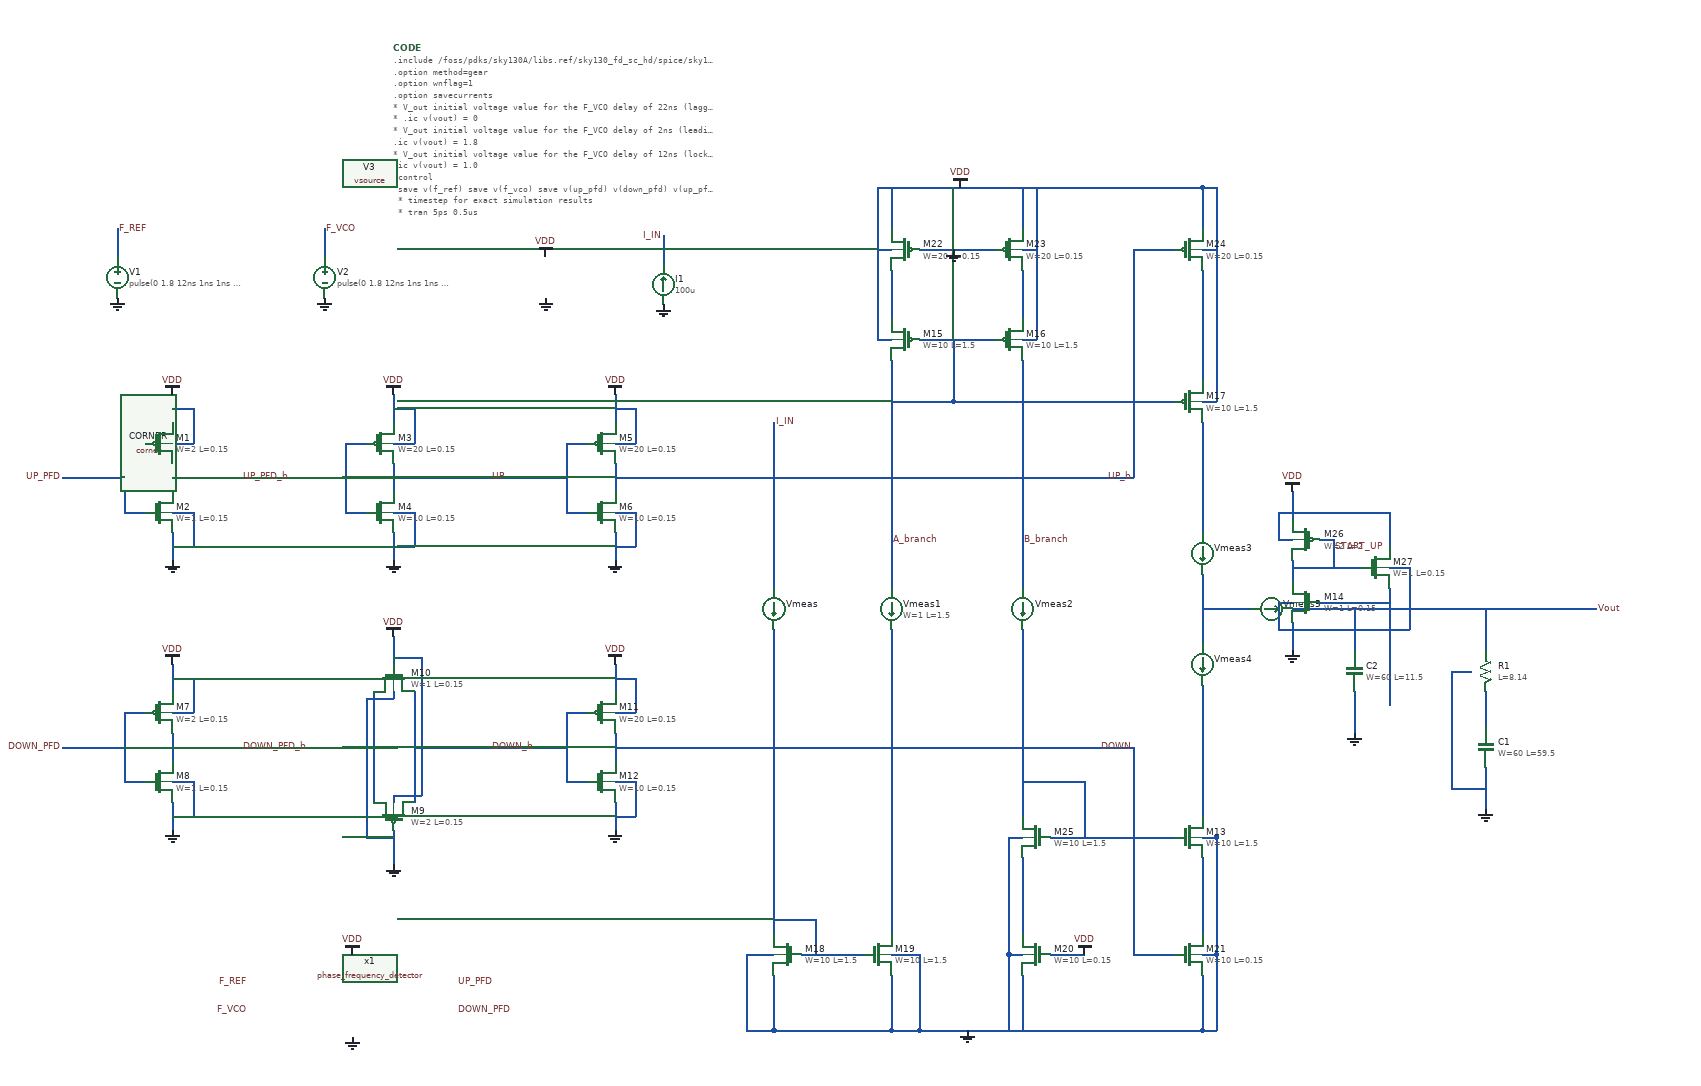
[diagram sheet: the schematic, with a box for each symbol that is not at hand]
v {xschem version=3.4.5 file_version=1.2
}
G {}
K {}
V {}
S {}
E {}
B 2 2530 -2160 3560 -1860 {flags=graph
y1=0
y2=1.8
ypos1=0
ypos2=2
divy=5
subdivy=1
unity=1
x1=2.1214896e-07
x2=2.1451015e-07
divx=5
subdivx=1
xlabmag=1.0
ylabmag=1.0


dataset=-1
unitx=1
logx=0
logy=0








linewidth_mult=5


color="6 7"
node="f_ref
f_vco"}
B 2 2530 -1840 3560 -1540 {flags=graph
y1=-0.038
y2=1.9
ypos1=0
ypos2=2
divy=5
subdivy=1
unity=1
x1=2.1214896e-07
x2=2.1451015e-07
divx=5
subdivx=1
xlabmag=1.0
ylabmag=1.0


dataset=-1
unitx=1
logx=0
logy=0








linewidth_mult=5


color="6 7"
node="up_pfd
down_pfd"}
B 2 2530 -1520 3560 -1220 {flags=graph
y1=-0.17312349
y2=1.9868765
ypos1=0
ypos2=2
divy=5
subdivy=1
unity=1
x1=2.1214896e-07
x2=2.1451015e-07
divx=5
subdivx=1
xlabmag=1.0
ylabmag=1.0


dataset=-1
unitx=1
logx=0
logy=0








linewidth_mult=5


color="6 7"
node="up_pfd_b
down_pfd_b"}
B 2 2530 -1200 3560 -900 {flags=graph
y1=-0.015
y2=1.9
ypos1=0
ypos2=2
divy=5
subdivy=1
unity=1
x1=2.1214896e-07
x2=2.1451015e-07
divx=5
subdivx=1
xlabmag=1.0
ylabmag=1.0


dataset=-1
unitx=1
logx=0
logy=0








linewidth_mult=5


color="6 7"
node="up
down_b"}
B 2 2530 -880 3560 -580 {flags=graph
y1=-0.012
y2=1.9
ypos1=0
ypos2=2
divy=5
subdivy=1
unity=1
x1=2.1214896e-07
x2=2.1451015e-07
divx=5
subdivx=1
xlabmag=1.0
ylabmag=1.0


dataset=-1
unitx=1
logx=0
logy=0








linewidth_mult=5


color="6 7"
node="up_b
down"}
B 2 3740 -2160 4770 -1860 {flags=graph
y1=-0.00062
y2=0.0001
ypos1=0
ypos2=2
divy=5
subdivy=1
unity=1
x1=2.1214896e-07
x2=2.1451015e-07
divx=5
subdivx=1
xlabmag=1.0
ylabmag=1.0


dataset=-1
unitx=1
logx=0
logy=0








linewidth_mult=5



color="6 7"
node="i(vmeas3)
i(vmeas4)"}
B 2 3740 -1840 4770 -1540 {flags=graph
y1=4.1e-15
y2=0.0016
ypos1=0
ypos2=2
divy=5
subdivy=1
unity=1
x1=2.1214896e-07
x2=2.1451015e-07
divx=5
subdivx=1
xlabmag=1.0
ylabmag=1.0


dataset=-1
unitx=1
logx=0
logy=0








linewidth_mult=5



color="6 7"
node="i(@m.xm24.msky130_fd_pr__pfet_01v8[id])
i(@m.xm21.msky130_fd_pr__nfet_01v8[id])"}
B 2 3740 -1520 4770 -1220 {flags=graph
y1=3.1e-12
y2=5.6e-05
ypos1=0
ypos2=2
divy=5
subdivy=1
unity=1
x1=2.1214896e-07
x2=2.1451015e-07
divx=5
subdivx=1
xlabmag=1.0
ylabmag=1.0


dataset=-1
unitx=1
logx=0
logy=0








linewidth_mult=5


color="6 7"
node="i(@m.xm17.msky130_fd_pr__pfet_01v8[id])
i(@m.xm13.msky130_fd_pr__nfet_01v8[id])"}
B 2 3740 -1200 4770 -900 {flags=graph
y1=-0.00035
y2=0.00021
ypos1=0
ypos2=2
divy=5
subdivy=1
unity=1
x1=2.1214896e-07
x2=2.1451015e-07
divx=5
subdivx=1
xlabmag=1.0
ylabmag=1.0


dataset=-1
unitx=1
logx=0
logy=0








linewidth_mult=5




color=6
node="\\"i(vmeas3) i(vmeas4) - \\""}
B 2 3740 -880 4770 -580 {flags=graph
y1=0.97
y2=1.2
ypos1=0
ypos2=2
divy=5
subdivy=1
unity=1
x1=2.1214896e-07
x2=2.1451015e-07
divx=5
subdivx=1
xlabmag=1.0
ylabmag=1.0


dataset=-1
unitx=1
logx=0
logy=0








linewidth_mult=5



color=6
node=vout}
N 2210 -1310 2210 -1260 {
lab=#net1}
N 2210 -1430 2210 -1370 {
lab=Vout}
N 2210 -1200 2210 -1140 {
lab=GND}
N 2160 -1340 2190 -1340 {
lab=GND}
N 2160 -1340 2160 -1170 {
lab=GND}
N 2160 -1170 2210 -1170 {
lab=GND}
N 2020 -1430 2020 -1370 {
lab=Vout}
N 2020 -1310 2020 -1250 {
lab=GND}
N 230 -1980 230 -1940 {
lab=F_REF}
N 530 -1980 530 -1940 {
lab=F_VCO}
N 1930 -1430 2370 -1430 {
lab=Vout}
N 1020 -1970 1020 -1930 {
lab=I_IN}
N 1800 -1430 1870 -1430 {
lab=#net2}
N 1220 -930 1310 -930 {
lab=#net3}
N 1180 -900 1180 -820 {
lab=GND}
N 1180 -820 1350 -820 {
lab=GND}
N 1140 -930 1180 -930 {
lab=GND}
N 1140 -930 1140 -820 {
lab=GND}
N 1140 -820 1180 -820 {
lab=GND}
N 1390 -930 1390 -820 {
lab=GND}
N 1350 -900 1350 -820 {
lab=GND}
N 1240 -980 1240 -930 {
lab=#net3}
N 1350 -820 1390 -820 {
lab=GND}
N 1180 -1700 1180 -1650 {
lab=I_IN}
N 1180 -1650 1180 -1460 {
lab=I_IN}
N 1620 -2040 1800 -2040 {
lab=VDD}
N 1800 -2040 1820 -2040 {
lab=VDD}
N 1390 -820 1700 -820 {
lab=GND}
N 1700 -820 1800 -820 {
lab=GND}
N 1820 -930 1820 -820 {
lab=GND}
N 1800 -820 1820 -820 {
lab=GND}
N 1800 -1730 1820 -1730 {
lab=VDD}
N 1800 -930 1820 -930 {
lab=GND}
N 1350 -930 1390 -930 {
lab=GND}
N 1330 -2040 1620 -2040 {
lab=VDD}
N 1520 -930 1540 -930 {
lab=GND}
N 1390 -1820 1500 -1820 {
lab=A_branch}
N 1440 -1820 1440 -1730 {
lab=A_branch}
N 1540 -1820 1560 -1820 {
lab=VDD}
N 1800 -1450 1800 -1380 {
lab=#net2}
N 1520 -930 1520 -820 {
lab=GND}
N 1800 -1480 1800 -1450 {
lab=#net2}
N 410 -1620 510 -1620 {
lab=UP_PFD_b}
N 410 -1230 600 -1230 {
lab=DOWN_PFD_b}
N 150 -1230 190 -1230 {
lab=DOWN_PFD}
N 150 -1620 190 -1620 {
lab=UP_PFD}
N 600 -1310 600 -1150 {
lab=DOWN_PFD_b}
N 660 -1310 660 -1150 {
lab=DOWN_b}
N 630 -1390 630 -1350 {
lab=VDD}
N 630 -1160 630 -1150 {
lab=VDD}
N 630 -1160 670 -1160 {
lab=VDD}
N 670 -1360 670 -1160 {
lab=VDD}
N 630 -1360 670 -1360 {
lab=VDD}
N 630 -1310 630 -1300 {
lab=GND}
N 590 -1300 630 -1300 {
lab=GND}
N 590 -1300 590 -1100 {
lab=GND}
N 590 -1100 630 -1100 {
lab=GND}
N 630 -1110 630 -1060 {
lab=GND}
N 310 -1640 310 -1600 {
lab=UP_PFD_b}
N 240 -1670 270 -1670 {
lab=UP_PFD}
N 240 -1670 240 -1570 {
lab=UP_PFD}
N 240 -1570 270 -1570 {
lab=UP_PFD}
N 310 -1230 410 -1230 {
lab=DOWN_PFD_b}
N 190 -1620 240 -1620 {
lab=UP_PFD}
N 310 -1540 310 -1500 {
lab=GND}
N 310 -1740 310 -1700 {
lab=VDD}
N 310 -1670 340 -1670 {
lab=VDD}
N 340 -1720 340 -1670 {
lab=VDD}
N 310 -1720 340 -1720 {
lab=VDD}
N 310 -1570 340 -1570 {
lab=GND}
N 340 -1570 340 -1520 {
lab=GND}
N 310 -1520 340 -1520 {
lab=GND}
N 310 -1250 310 -1210 {
lab=DOWN_PFD_b}
N 240 -1280 270 -1280 {
lab=DOWN_PFD}
N 240 -1280 240 -1180 {
lab=DOWN_PFD}
N 240 -1180 270 -1180 {
lab=DOWN_PFD}
N 310 -1620 410 -1620 {
lab=UP_PFD_b}
N 190 -1230 240 -1230 {
lab=DOWN_PFD}
N 310 -1150 310 -1110 {
lab=GND}
N 310 -1350 310 -1310 {
lab=VDD}
N 310 -1280 340 -1280 {
lab=VDD}
N 340 -1330 340 -1280 {
lab=VDD}
N 310 -1330 340 -1330 {
lab=VDD}
N 310 -1180 340 -1180 {
lab=GND}
N 340 -1180 340 -1130 {
lab=GND}
N 310 -1130 340 -1130 {
lab=GND}
N 630 -1640 630 -1600 {
lab=UP}
N 560 -1670 590 -1670 {
lab=UP_PFD_b}
N 560 -1670 560 -1570 {
lab=UP_PFD_b}
N 560 -1570 590 -1570 {
lab=UP_PFD_b}
N 630 -1540 630 -1500 {
lab=GND}
N 630 -1740 630 -1700 {
lab=VDD}
N 630 -1670 660 -1670 {
lab=VDD}
N 660 -1720 660 -1670 {
lab=VDD}
N 630 -1720 660 -1720 {
lab=VDD}
N 630 -1570 660 -1570 {
lab=GND}
N 660 -1570 660 -1520 {
lab=GND}
N 630 -1520 660 -1520 {
lab=GND}
N 1180 -1030 1180 -960 {
lab=#net3}
N 1180 -1400 1180 -1090 {
lab=#net3}
N 1350 -1030 1350 -960 {
lab=#net4}
N 1350 -1400 1350 -1090 {
lab=#net4}
N 1350 -1730 1440 -1730 {
lab=A_branch}
N 1180 -980 1240 -980 {
lab=#net3}
N 1180 -1090 1180 -1030 {
lab=#net3}
N 1350 -1090 1350 -1030 {
lab=#net4}
N 1440 -1730 1760 -1730 {
lab=A_branch}
N 950 -1640 950 -1600 {
lab=UP_b}
N 880 -1670 910 -1670 {
lab=UP}
N 880 -1670 880 -1570 {
lab=UP}
N 880 -1570 910 -1570 {
lab=UP}
N 950 -1540 950 -1500 {
lab=GND}
N 950 -1740 950 -1700 {
lab=VDD}
N 950 -1670 980 -1670 {
lab=VDD}
N 980 -1720 980 -1670 {
lab=VDD}
N 950 -1720 980 -1720 {
lab=VDD}
N 950 -1570 980 -1570 {
lab=GND}
N 980 -1570 980 -1520 {
lab=GND}
N 950 -1520 980 -1520 {
lab=GND}
N 950 -1250 950 -1210 {
lab=DOWN}
N 880 -1280 910 -1280 {
lab=DOWN_b}
N 880 -1280 880 -1180 {
lab=DOWN_b}
N 880 -1180 910 -1180 {
lab=DOWN_b}
N 950 -1150 950 -1110 {
lab=GND}
N 950 -1350 950 -1310 {
lab=VDD}
N 950 -1280 980 -1280 {
lab=VDD}
N 980 -1330 980 -1280 {
lab=VDD}
N 950 -1330 980 -1330 {
lab=VDD}
N 950 -1180 980 -1180 {
lab=GND}
N 980 -1180 980 -1130 {
lab=GND}
N 950 -1130 980 -1130 {
lab=GND}
N 630 -1620 880 -1620 {
lab=UP}
N 660 -1230 880 -1230 {
lab=DOWN_b}
N 950 -1620 1700 -1620 {
lab=UP_b}
N 950 -1230 1700 -1230 {
lab=DOWN}
N 510 -1620 560 -1620 {
lab=UP_PFD_b}
N 1540 -900 1540 -820 {
lab=GND}
N 1800 -900 1800 -820 {
lab=GND}
N 1800 -1920 1800 -1760 {
lab=#net5}
N 1820 -1920 1820 -1730 {
lab=VDD}
N 1540 -1790 1540 -1460 {
lab=B_branch}
N 1540 -1920 1540 -1850 {
lab=#net6}
N 1350 -1790 1350 -1460 {
lab=A_branch}
N 1350 -1920 1350 -1850 {
lab=#net7}
N 1560 -1920 1560 -1820 {
lab=VDD}
N 1330 -1920 1330 -1820 {
lab=VDD}
N 1330 -1820 1350 -1820 {
lab=VDD}
N 1390 -1950 1500 -1950 {
lab=GND}
N 1540 -1950 1560 -1950 {
lab=VDD}
N 1330 -1950 1350 -1950 {
lab=VDD}
N 1560 -2040 1560 -1920 {
lab=VDD}
N 1330 -2040 1330 -1920 {
lab=VDD}
N 1350 -2040 1350 -1980 {
lab=VDD}
N 1540 -2040 1540 -1980 {
lab=VDD}
N 1800 -1950 1820 -1950 {
lab=VDD}
N 1820 -2040 1820 -1920 {
lab=VDD}
N 1800 -2040 1800 -1980 {
lab=VDD}
N 1800 -1700 1800 -1540 {
lab=#net8}
N 1700 -1950 1700 -1620 {
lab=UP_b}
N 1700 -1950 1760 -1950 {
lab=UP_b}
N 1800 -1100 1820 -1100 {
lab=GND}
N 1520 -1100 1540 -1100 {
lab=GND}
N 1630 -1180 1630 -1100 {
lab=#net9}
N 1540 -1180 1630 -1180 {
lab=#net9}
N 1580 -1100 1760 -1100 {
lab=#net9}
N 1800 -1070 1800 -960 {
lab=#net10}
N 1820 -1100 1820 -930 {
lab=GND}
N 1540 -1070 1540 -960 {
lab=#net11}
N 1820 -1100 1820 -930 {
lab=GND}
N 1520 -1100 1520 -930 {
lab=GND}
N 1540 -1400 1540 -1130 {
lab=#net9}
N 1700 -1230 1700 -930 {
lab=DOWN}
N 1800 -1320 1800 -1130 {
lab=#net12}
N 1700 -930 1760 -930 {
lab=DOWN}
N 1580 -930 1630 -930 {
lab=VDD}
N 1930 -1500 1930 -1470 {
lab=START_UP}
N 1910 -1530 1930 -1530 {
lab=VDD}
N 1910 -1570 1910 -1530 {
lab=VDD}
N 1910 -1570 1930 -1570 {
lab=VDD}
N 1910 -1440 1930 -1440 {
lab=GND}
N 1910 -1440 1910 -1400 {
lab=GND}
N 1910 -1400 1930 -1400 {
lab=GND}
N 1930 -1490 2030 -1490 {
lab=START_UP}
N 2070 -1490 2100 -1490 {
lab=GND}
N 2100 -1490 2100 -1400 {
lab=GND}
N 1930 -1400 2100 -1400 {
lab=GND}
N 1970 -1530 1990 -1530 {
lab=START_UP}
N 1990 -1530 1990 -1490 {
lab=START_UP}
N 2070 -1460 2070 -1290 {
lab=#net3}
N 1970 -1440 2070 -1440 {
lab=#net3}
N 1930 -1570 2070 -1570 {
lab=VDD}
N 2070 -1570 2070 -1520 {
lab=VDD}
N 1930 -1410 1930 -1370 {
lab=GND}
N 1930 -1600 1930 -1560 {
lab=VDD}
C {sky130_fd_pr/corner.sym} 470 -2240 0 0 {name=CORNER only_toplevel=false corner=tt}
C {devices/code.sym} 630 -2241.25 0 0 {name=CODE only_toplevel=false value="

.include /foss/pdks/sky130A/libs.ref/sky130_fd_sc_hd/spice/sky130_fd_sc_hd.spice

.option method=gear
.option wnflag=1
.option savecurrents

* V_out initial voltage value for the F_VCO delay of 22ns (lagging)
* .ic v(vout) = 0

* V_out initial voltage value for the F_VCO delay of 2ns  (leading)
.ic v(vout) = 1.8

* V_out initial voltage value for the F_VCO delay of 12ns (lock condition)
.ic v(vout) = 1.0

.control
  save v(f_ref) save v(f_vco) save v(up_pfd) v(down_pfd) v(up_pfd_b) v(down_pfd_b) v(up) v(up_b) v(down) v(down_b) v(a_branch) v(b_branch) v(vout)
  
  * timestep for exact simulation results
  * tran 5ps 0.5us

  * timestep for faster simulation results
  tran 50ps 0.5us

  remzerovec
  write pfd_charge_pump_11.raw
  set appendwrite
.endc

"}
C {devices/vsource.sym} 850 -1910 0 0 {name=V3 value=1.8 savecurrent=false}
C {devices/gnd.sym} 850 -1880 0 0 {name=l2 lab=GND}
C {devices/vdd.sym} 850 -1940 0 1 {name=l3 lab=VDD}
C {devices/lab_wire.sym} 2370 -1430 0 1 {name=p9 sig_type=std_logic lab=Vout}
C {sky130_fd_pr/cap_mim_m3_1.sym} 2020 -1340 0 0 {name=C2 model=cap_mim_m3_1 W=60 L=11.5 MF=1 spiceprefix=X}
C {sky130_fd_pr/cap_mim_m3_1.sym} 2210 -1230 0 0 {name=C1 model=cap_mim_m3_1 W=60 L=59.5 MF=1 spiceprefix=X}
C {devices/gnd.sym} 2210 -1140 0 0 {name=l4 lab=GND}
C {devices/gnd.sym} 2020 -1250 0 0 {name=l9 lab=GND}
C {devices/vsource.sym} 230 -1910 0 0 {name=V1 value="pulse(0 1.8 12ns 1ns 1ns 24ns 50ns)" savecurrent=false
}
C {devices/gnd.sym} 230 -1880 0 0 {name=l10 lab=GND}
C {devices/lab_pin.sym} 230 -1980 0 1 {name=p11 sig_type=std_logic lab=F_REF}
C {devices/vsource.sym} 530 -1910 0 0 {name=V2 value="pulse(0 1.8 12ns 1ns 1ns 24ns 50ns)" savecurrent=false
* "sin(0.9 0.9 20.1MEG)" pulse(0 1.8 12ns 0.25ns 0.25ns 25ns 50ns)}
C {devices/gnd.sym} 530 -1880 0 0 {name=l15 lab=GND}
C {devices/lab_pin.sym} 530 -1980 0 1 {name=p12 sig_type=std_logic lab=F_VCO}
C {/foss/designs/my_design/projects/pll/pfd/xschem_ngspice/phase_frequency_detector.sym} 570 -870 0 0 {name=x1}
C {devices/lab_pin.sym} 420 -890 0 0 {name=p19 lab=F_REF}
C {devices/lab_pin.sym} 420 -850 0 0 {name=p20 lab=F_VCO}
C {devices/lab_wire.sym} 720 -890 0 1 {name=p22 sig_type=std_logic lab=UP_PFD}
C {devices/lab_wire.sym} 720 -850 2 0 {name=p23 sig_type=std_logic lab=DOWN_PFD}
C {devices/gnd.sym} 570 -810 0 0 {name=l1 lab=GND}
C {devices/vdd.sym} 570 -930 0 1 {name=l7 lab=VDD}
C {sky130_fd_pr/res_xhigh_po_0p35.sym} 2210 -1340 0 0 {name=R1
L=8.14
model=res_xhigh_po_0p35
spiceprefix=X
mult=1}
C {devices/isource.sym} 1020 -1900 2 0 {name=I1 value=100u}
C {devices/gnd.sym} 1020 -1870 0 0 {name=l11 lab=GND}
C {devices/lab_pin.sym} 1020 -1970 2 1 {name=p4 sig_type=std_logic lab=I_IN}
C {devices/ammeter.sym} 1900 -1430 3 0 {name=Vmeas5 savecurrent=true spice_ignore=0}
C {sky130_fd_pr/nfet_01v8.sym} 1200 -930 0 1 {name=M18
L=1.5
W=10
nf=1 
mult=10
ad="'int((nf+1)/2) * W/nf * 0.29'" 
pd="'2*int((nf+1)/2) * (W/nf + 0.29)'"
as="'int((nf+2)/2) * W/nf * 0.29'" 
ps="'2*int((nf+2)/2) * (W/nf + 0.29)'"
nrd="'0.29 / W'" nrs="'0.29 / W'"
sa=0 sb=0 sd=0
model=nfet_01v8
spiceprefix=X
}
C {sky130_fd_pr/nfet_01v8.sym} 1330 -930 0 0 {name=M19
L=1.5
W=10
nf=1 
mult=10
ad="'int((nf+1)/2) * W/nf * 0.29'" 
pd="'2*int((nf+1)/2) * (W/nf + 0.29)'"
as="'int((nf+2)/2) * W/nf * 0.29'" 
ps="'2*int((nf+2)/2) * (W/nf + 0.29)'"
nrd="'0.29 / W'" nrs="'0.29 / W'"
sa=0 sb=0 sd=0
model=nfet_01v8
spiceprefix=X
}
C {devices/gnd.sym} 1460 -820 0 0 {name=l14 lab=GND}
C {devices/ammeter.sym} 1180 -1430 0 0 {name=Vmeas savecurrent=true spice_ignore=0}
C {devices/ammeter.sym} 1800 -1510 0 0 {name=Vmeas3 savecurrent=true spice_ignore=0}
C {devices/ammeter.sym} 1800 -1350 0 0 {name=Vmeas4 savecurrent=true spice_ignore=0}
C {sky130_fd_pr/pfet_01v8.sym} 1780 -1730 0 0 {name=M17
L=1.5
W=10
nf=1
mult=20
ad="'int((nf+1)/2) * W/nf * 0.29'" 
pd="'2*int((nf+1)/2) * (W/nf + 0.29)'"
as="'int((nf+2)/2) * W/nf * 0.29'" 
ps="'2*int((nf+2)/2) * (W/nf + 0.29)'"
nrd="'0.29 / W'" nrs="'0.29 / W'"
sa=0 sb=0 sd=0
model=pfet_01v8
spiceprefix=X
}
C {sky130_fd_pr/nfet_01v8.sym} 1780 -930 0 0 {name=M21
L=0.15
W=10
nf=1 
mult=1
ad="'int((nf+1)/2) * W/nf * 0.29'" 
pd="'2*int((nf+1)/2) * (W/nf + 0.29)'"
as="'int((nf+2)/2) * W/nf * 0.29'" 
ps="'2*int((nf+2)/2) * (W/nf + 0.29)'"
nrd="'0.29 / W'" nrs="'0.29 / W'"
sa=0 sb=0 sd=0
model=nfet_01v8
spiceprefix=X
}
C {sky130_fd_pr/nfet_01v8.sym} 1560 -930 0 1 {name=M20
L=0.15
W=10
nf=1 
mult=1
ad="'int((nf+1)/2) * W/nf * 0.29'" 
pd="'2*int((nf+1)/2) * (W/nf + 0.29)'"
as="'int((nf+2)/2) * W/nf * 0.29'" 
ps="'2*int((nf+2)/2) * (W/nf + 0.29)'"
nrd="'0.29 / W'" nrs="'0.29 / W'"
sa=0 sb=0 sd=0
model=nfet_01v8
spiceprefix=X
}
C {sky130_fd_pr/pfet_01v8.sym} 1370 -1820 0 1 {name=M15
L=1.5
W=10
nf=1
mult=20
ad="'int((nf+1)/2) * W/nf * 0.29'" 
pd="'2*int((nf+1)/2) * (W/nf + 0.29)'"
as="'int((nf+2)/2) * W/nf * 0.29'" 
ps="'2*int((nf+2)/2) * (W/nf + 0.29)'"
nrd="'0.29 / W'" nrs="'0.29 / W'"
sa=0 sb=0 sd=0
model=pfet_01v8
spiceprefix=X
}
C {sky130_fd_pr/pfet_01v8.sym} 1520 -1820 0 0 {name=M16
L=1.5
W=10
nf=1
mult=20
ad="'int((nf+1)/2) * W/nf * 0.29'" 
pd="'2*int((nf+1)/2) * (W/nf + 0.29)'"
as="'int((nf+2)/2) * W/nf * 0.29'" 
ps="'2*int((nf+2)/2) * (W/nf + 0.29)'"
nrd="'0.29 / W'" nrs="'0.29 / W'"
sa=0 sb=0 sd=0
model=pfet_01v8
spiceprefix=X
}
C {devices/vdd.sym} 1450 -2040 0 1 {name=l6 lab=VDD}
C {devices/ammeter.sym} 1350 -1430 0 0 {name=Vmeas1 savecurrent=true spice_ignore=0
L=1.5
W=1
nf=1}
C {devices/ammeter.sym} 1540 -1430 0 0 {name=Vmeas2 savecurrent=true spice_ignore=0}
C {devices/lab_wire.sym} 1700 -1620 0 0 {name=p5 sig_type=std_logic lab=UP_b
L=1.5
W=10
nf=1
mult=30}
C {devices/lab_wire.sym} 1700 -1230 2 1 {name=p6 sig_type=std_logic lab=DOWN
W=10
nf=1
L=1.5
mult=12}
C {devices/lab_wire.sym} 1180 -1700 0 1 {name=p8 sig_type=std_logic lab=I_IN}
C {devices/lab_wire.sym} 410 -1620 0 1 {name=p1 sig_type=std_logic lab=UP_PFD_b}
C {devices/lab_wire.sym} 150 -1620 0 0 {name=p28 sig_type=std_logic lab=UP_PFD}
C {devices/lab_wire.sym} 150 -1230 2 1 {name=p29 sig_type=std_logic lab=DOWN_PFD}
C {sky130_fd_pr/pfet_01v8.sym} 630 -1130 3 0 {name=M9
L=0.15
W=2
nf=2
mult=1
ad="'int((nf+1)/2) * W/nf * 0.29'" 
pd="'2*int((nf+1)/2) * (W/nf + 0.29)'"
as="'int((nf+2)/2) * W/nf * 0.29'" 
ps="'2*int((nf+2)/2) * (W/nf + 0.29)'"
nrd="'0.29 / W'" nrs="'0.29 / W'"
sa=0 sb=0 sd=0
model=pfet_01v8
spiceprefix=X
}
C {sky130_fd_pr/nfet_01v8.sym} 630 -1330 1 0 {name=M10
L=0.15
W=1
nf=1 
mult=1
ad="'int((nf+1)/2) * W/nf * 0.29'" 
pd="'2*int((nf+1)/2) * (W/nf + 0.29)'"
as="'int((nf+2)/2) * W/nf * 0.29'" 
ps="'2*int((nf+2)/2) * (W/nf + 0.29)'"
nrd="'0.29 / W'" nrs="'0.29 / W'"
sa=0 sb=0 sd=0
model=nfet_01v8
spiceprefix=X
}
C {devices/vdd.sym} 630 -1390 0 0 {name=l19 lab=VDD}
C {devices/gnd.sym} 630 -1060 0 0 {name=l20 lab=GND}
C {sky130_fd_pr/pfet_01v8.sym} 290 -1670 0 0 {name=M1
L=0.15
W=2
nf=2
mult=1
ad="'int((nf+1)/2) * W/nf * 0.29'" 
pd="'2*int((nf+1)/2) * (W/nf + 0.29)'"
as="'int((nf+2)/2) * W/nf * 0.29'" 
ps="'2*int((nf+2)/2) * (W/nf + 0.29)'"
nrd="'0.29 / W'" nrs="'0.29 / W'"
sa=0 sb=0 sd=0
model=pfet_01v8
spiceprefix=X
}
C {sky130_fd_pr/nfet_01v8.sym} 290 -1570 2 1 {name=M2
L=0.15
W=1
nf=1 
mult=1
ad="'int((nf+1)/2) * W/nf * 0.29'" 
pd="'2*int((nf+1)/2) * (W/nf + 0.29)'"
as="'int((nf+2)/2) * W/nf * 0.29'" 
ps="'2*int((nf+2)/2) * (W/nf + 0.29)'"
nrd="'0.29 / W'" nrs="'0.29 / W'"
sa=0 sb=0 sd=0
model=nfet_01v8
spiceprefix=X
}
C {devices/gnd.sym} 310 -1500 0 0 {name=l21 lab=GND}
C {devices/vdd.sym} 310 -1740 0 0 {name=l22 lab=VDD}
C {sky130_fd_pr/pfet_01v8.sym} 290 -1280 0 0 {name=M7
L=0.15
W=2
nf=2
mult=1
ad="'int((nf+1)/2) * W/nf * 0.29'" 
pd="'2*int((nf+1)/2) * (W/nf + 0.29)'"
as="'int((nf+2)/2) * W/nf * 0.29'" 
ps="'2*int((nf+2)/2) * (W/nf + 0.29)'"
nrd="'0.29 / W'" nrs="'0.29 / W'"
sa=0 sb=0 sd=0
model=pfet_01v8
spiceprefix=X
}
C {sky130_fd_pr/nfet_01v8.sym} 290 -1180 2 1 {name=M8
L=0.15
W=1
nf=1 
mult=1
ad="'int((nf+1)/2) * W/nf * 0.29'" 
pd="'2*int((nf+1)/2) * (W/nf + 0.29)'"
as="'int((nf+2)/2) * W/nf * 0.29'" 
ps="'2*int((nf+2)/2) * (W/nf + 0.29)'"
nrd="'0.29 / W'" nrs="'0.29 / W'"
sa=0 sb=0 sd=0
model=nfet_01v8
spiceprefix=X
}
C {devices/gnd.sym} 310 -1110 0 0 {name=l23 lab=GND}
C {devices/vdd.sym} 310 -1350 0 0 {name=l24 lab=VDD}
C {sky130_fd_pr/pfet_01v8.sym} 610 -1670 0 0 {name=M3
L=0.15
W=20
nf=2
mult=1
ad="'int((nf+1)/2) * W/nf * 0.29'" 
pd="'2*int((nf+1)/2) * (W/nf + 0.29)'"
as="'int((nf+2)/2) * W/nf * 0.29'" 
ps="'2*int((nf+2)/2) * (W/nf + 0.29)'"
nrd="'0.29 / W'" nrs="'0.29 / W'"
sa=0 sb=0 sd=0
model=pfet_01v8
spiceprefix=X
}
C {sky130_fd_pr/nfet_01v8.sym} 610 -1570 2 1 {name=M4
L=0.15
W=10
nf=1 
mult=1
ad="'int((nf+1)/2) * W/nf * 0.29'" 
pd="'2*int((nf+1)/2) * (W/nf + 0.29)'"
as="'int((nf+2)/2) * W/nf * 0.29'" 
ps="'2*int((nf+2)/2) * (W/nf + 0.29)'"
nrd="'0.29 / W'" nrs="'0.29 / W'"
sa=0 sb=0 sd=0
model=nfet_01v8
spiceprefix=X
}
C {devices/gnd.sym} 630 -1500 0 0 {name=l25 lab=GND}
C {devices/vdd.sym} 630 -1740 0 0 {name=l26 lab=VDD}
C {devices/lab_wire.sym} 410 -1230 2 0 {name=p2 sig_type=std_logic lab=DOWN_PFD_b}
C {devices/lab_wire.sym} 1540 -1530 0 1 {name=p3 sig_type=std_logic lab=B_branch}
C {devices/lab_wire.sym} 1350 -1530 0 1 {name=p10 sig_type=std_logic lab=A_branch}
C {sky130_fd_pr/pfet_01v8.sym} 930 -1670 0 0 {name=M5
L=0.15
W=20
nf=1
mult=1
ad="'int((nf+1)/2) * W/nf * 0.29'" 
pd="'2*int((nf+1)/2) * (W/nf + 0.29)'"
as="'int((nf+2)/2) * W/nf * 0.29'" 
ps="'2*int((nf+2)/2) * (W/nf + 0.29)'"
nrd="'0.29 / W'" nrs="'0.29 / W'"
sa=0 sb=0 sd=0
model=pfet_01v8
spiceprefix=X
}
C {sky130_fd_pr/nfet_01v8.sym} 930 -1570 2 1 {name=M6
L=0.15
W=10
nf=1 
mult=1
ad="'int((nf+1)/2) * W/nf * 0.29'" 
pd="'2*int((nf+1)/2) * (W/nf + 0.29)'"
as="'int((nf+2)/2) * W/nf * 0.29'" 
ps="'2*int((nf+2)/2) * (W/nf + 0.29)'"
nrd="'0.29 / W'" nrs="'0.29 / W'"
sa=0 sb=0 sd=0
model=nfet_01v8
spiceprefix=X
}
C {devices/gnd.sym} 950 -1500 0 0 {name=l5 lab=GND}
C {devices/vdd.sym} 950 -1740 0 0 {name=l8 lab=VDD}
C {sky130_fd_pr/pfet_01v8.sym} 930 -1280 0 0 {name=M11
L=0.15
W=20
nf=1
mult=1
ad="'int((nf+1)/2) * W/nf * 0.29'" 
pd="'2*int((nf+1)/2) * (W/nf + 0.29)'"
as="'int((nf+2)/2) * W/nf * 0.29'" 
ps="'2*int((nf+2)/2) * (W/nf + 0.29)'"
nrd="'0.29 / W'" nrs="'0.29 / W'"
sa=0 sb=0 sd=0
model=pfet_01v8
spiceprefix=X
}
C {sky130_fd_pr/nfet_01v8.sym} 930 -1180 2 1 {name=M12
L=0.15
W=10
nf=1 
mult=1
ad="'int((nf+1)/2) * W/nf * 0.29'" 
pd="'2*int((nf+1)/2) * (W/nf + 0.29)'"
as="'int((nf+2)/2) * W/nf * 0.29'" 
ps="'2*int((nf+2)/2) * (W/nf + 0.29)'"
nrd="'0.29 / W'" nrs="'0.29 / W'"
sa=0 sb=0 sd=0
model=nfet_01v8
spiceprefix=X
}
C {devices/gnd.sym} 950 -1110 0 0 {name=l12 lab=GND}
C {devices/vdd.sym} 950 -1350 0 0 {name=l13 lab=VDD}
C {devices/lab_wire.sym} 770 -1620 0 1 {name=p13 sig_type=std_logic lab=UP}
C {devices/lab_wire.sym} 770 -1230 2 0 {name=p14 sig_type=std_logic lab=DOWN_b}
C {sky130_fd_pr/pfet_01v8.sym} 1370 -1950 0 1 {name=M22
L=0.15
W=20
nf=1
mult=1
ad="'int((nf+1)/2) * W/nf * 0.29'" 
pd="'2*int((nf+1)/2) * (W/nf + 0.29)'"
as="'int((nf+2)/2) * W/nf * 0.29'" 
ps="'2*int((nf+2)/2) * (W/nf + 0.29)'"
nrd="'0.29 / W'" nrs="'0.29 / W'"
sa=0 sb=0 sd=0
model=pfet_01v8
spiceprefix=X
}
C {sky130_fd_pr/pfet_01v8.sym} 1520 -1950 0 0 {name=M23
L=0.15
W=20
nf=1
mult=1
ad="'int((nf+1)/2) * W/nf * 0.29'" 
pd="'2*int((nf+1)/2) * (W/nf + 0.29)'"
as="'int((nf+2)/2) * W/nf * 0.29'" 
ps="'2*int((nf+2)/2) * (W/nf + 0.29)'"
nrd="'0.29 / W'" nrs="'0.29 / W'"
sa=0 sb=0 sd=0
model=pfet_01v8
spiceprefix=X
}
C {sky130_fd_pr/pfet_01v8.sym} 1780 -1950 0 0 {name=M24
L=0.15
W=20
nf=1
mult=1
ad="'int((nf+1)/2) * W/nf * 0.29'" 
pd="'2*int((nf+1)/2) * (W/nf + 0.29)'"
as="'int((nf+2)/2) * W/nf * 0.29'" 
ps="'2*int((nf+2)/2) * (W/nf + 0.29)'"
nrd="'0.29 / W'" nrs="'0.29 / W'"
sa=0 sb=0 sd=0
model=pfet_01v8
spiceprefix=X
}
C {devices/gnd.sym} 1440 -1950 0 0 {name=l16 lab=GND}
C {sky130_fd_pr/nfet_01v8.sym} 1780 -1100 0 0 {name=M13
L=1.5
W=10
nf=1 
mult=10
ad="'int((nf+1)/2) * W/nf * 0.29'" 
pd="'2*int((nf+1)/2) * (W/nf + 0.29)'"
as="'int((nf+2)/2) * W/nf * 0.29'" 
ps="'2*int((nf+2)/2) * (W/nf + 0.29)'"
nrd="'0.29 / W'" nrs="'0.29 / W'"
sa=0 sb=0 sd=0
model=nfet_01v8
spiceprefix=X
}
C {sky130_fd_pr/nfet_01v8.sym} 1560 -1100 0 1 {name=M25
L=1.5
W=10
nf=1 
mult=10
ad="'int((nf+1)/2) * W/nf * 0.29'" 
pd="'2*int((nf+1)/2) * (W/nf + 0.29)'"
as="'int((nf+2)/2) * W/nf * 0.29'" 
ps="'2*int((nf+2)/2) * (W/nf + 0.29)'"
nrd="'0.29 / W'" nrs="'0.29 / W'"
sa=0 sb=0 sd=0
model=nfet_01v8
spiceprefix=X
}
C {devices/vdd.sym} 1630 -930 0 1 {name=l17 lab=VDD}
C {sky130_fd_pr/nfet_01v8.sym} 1950 -1440 0 1 {name=M14
L=0.15
W=1
nf=1 
mult=1
ad="'int((nf+1)/2) * W/nf * 0.29'" 
pd="'2*int((nf+1)/2) * (W/nf + 0.29)'"
as="'int((nf+2)/2) * W/nf * 0.29'" 
ps="'2*int((nf+2)/2) * (W/nf + 0.29)'"
nrd="'0.29 / W'" nrs="'0.29 / W'"
sa=0 sb=0 sd=0
model=nfet_01v8
spiceprefix=X
}
C {sky130_fd_pr/pfet_01v8.sym} 1950 -1530 0 1 {name=M26
L=2
W=2
nf=1
mult=1
ad="'int((nf+1)/2) * W/nf * 0.29'" 
pd="'2*int((nf+1)/2) * (W/nf + 0.29)'"
as="'int((nf+2)/2) * W/nf * 0.29'" 
ps="'2*int((nf+2)/2) * (W/nf + 0.29)'"
nrd="'0.29 / W'" nrs="'0.29 / W'"
sa=0 sb=0 sd=0
model=pfet_01v8
spiceprefix=X
}
C {sky130_fd_pr/nfet_01v8.sym} 2050 -1490 0 0 {name=M27
L=0.15
W=1
nf=1 
mult=1
ad="'int((nf+1)/2) * W/nf * 0.29'" 
pd="'2*int((nf+1)/2) * (W/nf + 0.29)'"
as="'int((nf+2)/2) * W/nf * 0.29'" 
ps="'2*int((nf+2)/2) * (W/nf + 0.29)'"
nrd="'0.29 / W'" nrs="'0.29 / W'"
sa=0 sb=0 sd=0
model=nfet_01v8
spiceprefix=X
}
C {devices/lab_wire.sym} 1990 -1520 0 1 {name=p7 sig_type=std_logic lab=START_UP}
C {devices/gnd.sym} 1930 -1370 0 0 {name=l30 lab=GND}
C {devices/vdd.sym} 1930 -1600 0 0 {name=l31 lab=VDD}
